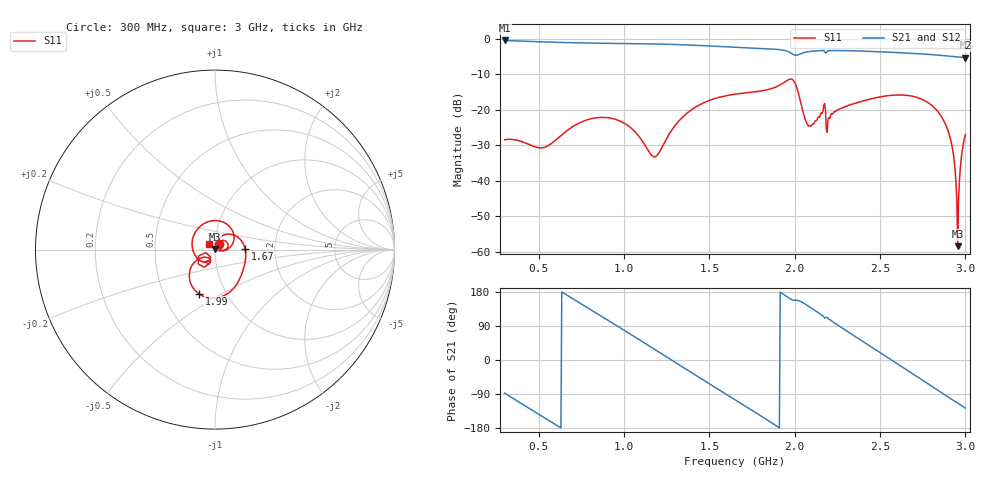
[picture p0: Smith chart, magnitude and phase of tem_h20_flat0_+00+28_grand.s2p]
! tem_h20_flat0_+00+28_grand
! simulated by sim/fixtures_fdtd.py (S12 = S21, S22 not computed)
# HZ S RI R 50
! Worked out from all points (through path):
!   541 points, 300 MHz to 3 GHz, reference 50 ohm
!   highest |S21| = -0.48 dB at 300 MHz (marker M1); lowest = -5.3 dB at 3 GHz (marker M2)
!   group delay of S21, straight-line fit = 777 ps
!   lowest |S11| = -58.4 dB at 2.955 GHz (marker M3), VSWR 1.00, Z = 50 + j0.116 ohm
!   |S11| at or under -10 dB: start of sweep to end of sweep
!   |S22| runs from - to - dB; largest |S21 - S12| = 0
!   S11 on the Smith chart (normalised r, x): 300 MHz: 1.05, +0.06; 1.67 GHz: 1.40, +0.01; 1.99 GHz: 0.75, -0.40; 3 GHz: 0.94, +0.06
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3e8  0.0239 0.0294  0.0433 -0.9456  0.0433 -0.9456  0 0
5.4e8  0.0187 0.0235  -0.8116 -0.3903  -0.8116 -0.3903  0 0
7.5e8  0.0435 0.0515  -0.74 0.4654  -0.74 0.4654  0 0
9.75e8  0.0691 0.00852  0.0656 0.8562  0.0656 0.8562  0 0
1.2e9  0.0153 0.0185  0.7807 0.3187  0.7807 0.3187  0 0
1.32e9  0.0257 0.0642  0.8089 -0.1712  0.8089 -0.1712  0 0
1.455e9  0.0865 0.0858  0.5124 -0.6161  0.5124 -0.6161  0 0
1.65e9  0.1651 0.0144  -0.1959 -0.734  -0.1959 -0.734  0 0
1.67e9  0.1682 0.0029  -0.265 -0.7078  -0.265 -0.7078  0 0
1.855e9  0.1541 -0.1202  -0.6871 -0.2137  -0.6871 -0.2137  0 0
1.99e9  -0.0896 -0.2466  -0.5592 0.2228  -0.5592 0.2228  0 0
2.07e9  -0.0487 -0.0438  -0.5352 0.3737  -0.5352 0.3737  0 0
2.1e9  -0.0269 -0.0547  -0.4831 0.4628  -0.4831 0.4628  0 0
2.17e9  -0.0596 -0.0981  -0.2731 0.6285  -0.2731 0.6285  0 0
2.195e9  -0.0332 -0.0648  -0.2295 0.6397  -0.2295 0.6397  0 0
2.305e9  -0.106 -0.0374  0.1583 0.6599  0.1583 0.6599  0 0
2.55e9  -0.053 0.1488  0.645 0.0559  0.645 0.0559  0 0
2.855e9  0.0824 0.0117  0.0535 -0.5812  0.0535 -0.5812  0 0
2.92e9  0.0314 -0.00734  -0.1347 -0.5482  -0.1347 -0.5482  0 0
2.955e9  0.000319 0.00116  -0.2248 -0.5068  -0.2248 -0.5068  0 0
2.98e9  -0.0189 0.0164  -0.2833 -0.4695  -0.2833 -0.4695  0 0
3e9  -0.0309 0.0324  -0.3261 -0.4345  -0.3261 -0.4345  0 0
